VERSION 5.8 ;
BUSBITCHARS "[]" ;
DIVIDERCHAR "/" ;
UNITS
    DATABASE MICRONS 1000 ;
END UNITS

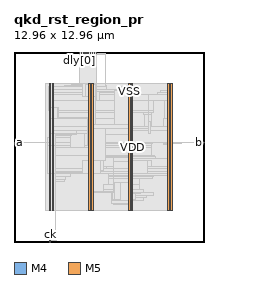
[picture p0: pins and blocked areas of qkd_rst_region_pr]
MACRO qkd_rst_region_pr
  FOREIGN qkd_rst_region_pr 0 0 ;
  CLASS BLOCK ;
  SIZE 12.96 BY 12.96 ;
  PIN a
    DIRECTION INPUT ;
    USE SIGNAL ;
    PORT
      LAYER M4 ;
        RECT  0 6.768 0.084 6.792 ;
    END
  END a
  PIN b
    DIRECTION OUTPUT ;
    USE SIGNAL ;
    PORT
      LAYER M4 ;
        RECT  12.876 6.768 12.96 6.792 ;
    END
  END b
  PIN ck
    DIRECTION INPUT ;
    USE SIGNAL ;
    PORT
      LAYER M5 ;
        RECT  2.448 0 2.472 0.084 ;
    END
  END ck
  PIN dly[0]
    DIRECTION INPUT ;
    USE SIGNAL ;
    PORT
      LAYER M5 ;
        RECT  4.464 12.876 4.488 12.96 ;
    END
  END dly[0]
  PIN dly[1]
    DIRECTION INPUT ;
    USE SIGNAL ;
    PORT
      LAYER M5 ;
        RECT  4.608 12.876 4.632 12.96 ;
    END
  END dly[1]
  PIN dly[2]
    DIRECTION INPUT ;
    USE SIGNAL ;
    PORT
      LAYER M5 ;
        RECT  4.752 12.876 4.776 12.96 ;
    END
  END dly[2]
  PIN dly[3]
    DIRECTION INPUT ;
    USE SIGNAL ;
    PORT
      LAYER M5 ;
        RECT  4.896 12.876 4.92 12.96 ;
    END
  END dly[3]
  PIN dly[4]
    DIRECTION INPUT ;
    USE SIGNAL ;
    PORT
      LAYER M5 ;
        RECT  5.04 12.876 5.064 12.96 ;
    END
  END dly[4]
  PIN dly[5]
    DIRECTION INPUT ;
    USE SIGNAL ;
    PORT
      LAYER M5 ;
        RECT  5.184 12.876 5.208 12.96 ;
    END
  END dly[5]
  PIN dly[6]
    DIRECTION INPUT ;
    USE SIGNAL ;
    PORT
      LAYER M5 ;
        RECT  5.328 12.876 5.352 12.96 ;
    END
  END dly[6]
  PIN dly[7]
    DIRECTION INPUT ;
    USE SIGNAL ;
    PORT
      LAYER M5 ;
        RECT  5.472 12.876 5.496 12.96 ;
    END
  END dly[7]
  PIN por_n
    DIRECTION INPUT ;
    USE SIGNAL ;
    PORT
      LAYER M5 ;
        RECT  5.616 12.876 5.64 12.96 ;
    END
  END por_n
  PIN VDD
    DIRECTION INOUT ;
    USE POWER ;
    PORT
      LAYER M5 ;
        RECT  10.692 2.151 10.812 10.809 ;
        RECT  7.992 2.151 8.112 10.809 ;
        RECT  5.292 2.151 5.412 10.809 ;
        RECT  2.592 2.151 2.712 10.809 ;
    END
  END VDD
  PIN VSS
    DIRECTION INOUT ;
    USE GROUND ;
    PORT
      LAYER M5 ;
        RECT  10.5 2.137 10.62 10.823 ;
        RECT  7.8 2.137 7.92 10.823 ;
        RECT  5.1 2.137 5.22 10.823 ;
        RECT  2.4 2.137 2.52 10.823 ;
    END
  END VSS
  OBS
    LAYER RVTN ;
     RECT  2.16 2.16 10.8 2.295 ;
     RECT  2.16 2.565 10.8 2.835 ;
     RECT  2.16 3.105 10.8 3.375 ;
     RECT  2.16 3.645 10.8 3.915 ;
     RECT  2.16 4.185 10.8 4.455 ;
     RECT  2.16 4.725 10.8 4.995 ;
     RECT  2.16 5.265 10.8 5.535 ;
     RECT  2.16 5.805 10.8 6.075 ;
     RECT  2.16 6.345 10.8 6.615 ;
     RECT  2.16 6.885 10.8 7.155 ;
     RECT  2.16 7.425 10.8 7.695 ;
     RECT  2.16 7.965 10.8 8.235 ;
     RECT  2.16 8.505 10.8 8.775 ;
     RECT  2.16 9.045 10.8 9.315 ;
     RECT  2.16 9.585 10.8 9.855 ;
     RECT  2.16 10.125 10.8 10.395 ;
     RECT  2.16 10.665 10.8 10.8 ;
    LAYER RVTP ;
     RECT  2.16 2.295 10.8 2.565 ;
     RECT  2.16 2.835 10.8 3.105 ;
     RECT  2.16 3.375 10.8 3.645 ;
     RECT  2.16 3.915 10.8 4.185 ;
     RECT  2.16 4.455 10.8 4.725 ;
     RECT  2.16 4.995 10.8 5.265 ;
     RECT  2.16 5.535 10.8 5.805 ;
     RECT  2.16 6.075 10.8 6.345 ;
     RECT  2.16 6.615 10.8 6.885 ;
     RECT  2.16 7.155 10.8 7.425 ;
     RECT  2.16 7.695 10.8 7.965 ;
     RECT  2.16 8.235 10.8 8.505 ;
     RECT  2.16 8.775 10.8 9.045 ;
     RECT  2.16 9.315 10.8 9.585 ;
     RECT  2.16 9.855 10.8 10.125 ;
     RECT  2.16 10.395 10.8 10.665 ;
    LAYER M1 ;
     RECT  2.16 2.151 10.8 10.809 ;
    LAYER M2 ;
     RECT  2.16 2.151 10.8 10.809 ;
     RECT  10.8 2.421 10.812 10.539 ;
     RECT  10.812 6.696 11.435 6.714 ;
    LAYER M3 ;
     RECT  2.415 2.143 2.505 2.413 ;
     RECT  5.115 2.143 5.205 2.413 ;
     RECT  7.815 2.143 7.905 2.413 ;
     RECT  10.515 2.143 10.605 2.413 ;
     RECT  7.815 2.413 8.097 2.569 ;
     RECT  6.804 2.569 8.097 2.641 ;
     RECT  6.66 2.641 8.097 2.839 ;
     RECT  6.66 2.839 8.802 3.037 ;
     RECT  6.66 3.037 9.054 3.181 ;
     RECT  6.66 3.181 9.522 3.403 ;
     RECT  6.12 3.403 9.522 3.407 ;
     RECT  6.12 3.407 8.838 3.569 ;
     RECT  6.12 3.569 8.586 3.911 ;
     RECT  2.415 2.413 2.697 4.117 ;
     RECT  2.415 4.117 3.33 4.153 ;
     RECT  2.415 4.153 3.438 4.261 ;
     RECT  6.444 3.911 8.586 4.351 ;
     RECT  2.415 4.261 3.546 4.495 ;
     RECT  6.444 4.351 9.45 4.495 ;
     RECT  6.444 4.495 9.522 4.531 ;
     RECT  10.515 2.413 10.797 4.531 ;
     RECT  5.115 2.413 5.397 4.657 ;
     RECT  6.444 4.531 10.797 4.657 ;
     RECT  5.115 4.657 10.797 4.699 ;
     RECT  2.415 4.495 3.834 4.801 ;
     RECT  4.716 4.699 10.797 4.801 ;
     RECT  2.415 4.801 10.797 5.027 ;
     RECT  6.336 5.027 10.797 5.729 ;
     RECT  6.336 5.729 9.63 5.837 ;
     RECT  6.336 5.837 9.558 5.873 ;
     RECT  2.415 5.027 5.598 5.881 ;
     RECT  6.336 5.873 9.378 5.881 ;
     RECT  2.415 5.881 9.378 6.449 ;
     RECT  2.415 6.449 3.87 6.571 ;
     RECT  4.788 6.449 9.378 6.605 ;
     RECT  10.515 5.729 10.797 6.655 ;
     RECT  5.115 6.605 9.378 6.691 ;
     RECT  10.188 6.655 10.797 6.691 ;
     RECT  2.412 6.571 3.87 6.763 ;
     RECT  10.188 6.691 11.43 6.797 ;
     RECT  5.115 6.691 9.45 6.817 ;
     RECT  10.188 6.797 10.797 6.817 ;
     RECT  2.304 6.763 3.87 7.115 ;
     RECT  2.415 7.115 3.87 7.231 ;
     RECT  2.415 7.231 3.906 7.357 ;
     RECT  2.415 7.357 4.23 7.591 ;
     RECT  5.115 6.817 10.797 7.591 ;
     RECT  2.415 7.591 10.797 7.889 ;
     RECT  10.224 7.889 10.797 8.429 ;
     RECT  8.892 7.889 9.378 8.671 ;
     RECT  2.415 7.889 8.097 8.851 ;
     RECT  8.82 8.671 9.378 8.851 ;
     RECT  2.415 8.851 9.522 8.941 ;
     RECT  2.376 8.941 9.522 9.661 ;
     RECT  10.26 8.429 10.797 9.661 ;
     RECT  2.376 9.661 10.797 10.049 ;
     RECT  9.216 10.049 10.797 10.085 ;
     RECT  2.376 10.049 8.478 10.229 ;
     RECT  9.756 10.085 10.797 10.229 ;
     RECT  10.008 10.229 10.797 10.355 ;
     RECT  2.376 10.229 8.097 10.427 ;
     RECT  7.092 10.427 8.097 10.463 ;
     RECT  7.164 10.463 8.097 10.547 ;
     RECT  10.515 10.355 10.797 10.547 ;
     RECT  2.376 10.427 6.318 10.589 ;
     RECT  7.164 10.547 7.905 10.589 ;
     RECT  2.376 10.589 2.505 10.625 ;
     RECT  3.24 10.589 5.31 10.625 ;
     RECT  3.42 10.625 5.31 10.661 ;
     RECT  6.228 10.589 6.318 10.661 ;
     RECT  7.704 10.589 7.905 10.661 ;
     RECT  3.924 10.661 5.31 10.769 ;
     RECT  4.248 10.769 5.31 10.781 ;
     RECT  2.415 10.625 2.505 10.817 ;
     RECT  7.815 10.661 7.905 10.817 ;
     RECT  10.515 10.547 10.605 10.817 ;
     RECT  4.248 10.781 5.274 10.829 ;
     RECT  4.572 10.829 5.274 10.973 ;
     RECT  4.572 10.973 4.662 12.029 ;
     RECT  4.644 12.029 4.662 12.845 ;
     RECT  6.228 10.661 6.246 12.845 ;
    LAYER M4 ;
     RECT  0.06 6.768 2.293 6.792 ;
     RECT  2.293 4.704 2.408 4.728 ;
     RECT  2.293 6.576 2.408 6.792 ;
     RECT  2.365 8.976 2.408 9 ;
     RECT  2.408 2.148 2.512 10.812 ;
     RECT  2.512 2.418 2.704 10.542 ;
     RECT  2.437 0.096 2.867 0.12 ;
     RECT  2.704 8.448 3.017 9.144 ;
     RECT  4.561 12 4.589 12.024 ;
     RECT  2.704 4.704 4.705 4.728 ;
     RECT  4.237 10.8 4.705 10.824 ;
     RECT  2.704 7.392 4.777 7.416 ;
     RECT  4.589 12 4.787 12.84 ;
     RECT  4.777 6.576 4.993 7.416 ;
     RECT  3.017 8.448 4.993 8.472 ;
     RECT  4.705 9.936 5.029 10.824 ;
     RECT  4.705 4.704 5.108 5.592 ;
     RECT  4.993 6.576 5.108 8.472 ;
     RECT  5.029 9.936 5.108 10.968 ;
     RECT  5.108 2.148 5.212 10.968 ;
     RECT  5.212 2.418 5.285 10.968 ;
     RECT  5.285 2.418 5.404 10.776 ;
     RECT  5.404 9.504 5.465 10.776 ;
     RECT  4.787 12.768 5.603 12.84 ;
     RECT  5.465 9.648 5.651 10.776 ;
     RECT  5.651 9.648 5.825 10.296 ;
     RECT  5.404 4.704 5.897 5.736 ;
     RECT  5.897 4.896 6.113 5.736 ;
     RECT  5.603 12.816 6.257 12.84 ;
     RECT  5.404 3.408 6.721 3.432 ;
     RECT  6.113 5.136 6.803 5.736 ;
     RECT  6.721 2.88 6.865 3.432 ;
     RECT  6.865 2.88 7.261 4.056 ;
     RECT  7.261 2.832 7.808 4.056 ;
     RECT  6.803 5.52 7.808 5.736 ;
     RECT  5.404 7.344 7.808 8.424 ;
     RECT  5.825 10.272 7.808 10.296 ;
     RECT  7.808 2.148 7.912 10.812 ;
     RECT  7.912 2.418 8.104 10.542 ;
     RECT  8.104 2.88 8.273 3.336 ;
     RECT  8.273 3.312 8.597 3.336 ;
     RECT  8.104 4.656 9.101 5.544 ;
     RECT  8.104 7.728 9.157 7.752 ;
     RECT  9.157 10.032 9.245 10.056 ;
     RECT  9.157 7.392 9.281 8.232 ;
     RECT  9.101 5.136 9.353 5.544 ;
     RECT  9.281 8.208 9.389 8.232 ;
     RECT  9.353 5.136 10.508 5.16 ;
     RECT  10.508 2.148 10.612 10.812 ;
     RECT  10.612 2.418 10.804 10.542 ;
     RECT  10.804 6.768 12.924 6.792 ;
    LAYER M5 ;
     RECT  2.448 0.016 2.472 0.085 ;
     RECT  2.448 0.085 2.856 0.131 ;
     RECT  2.832 0.131 2.856 2.137 ;
     RECT  5.1 2.137 5.22 2.151 ;
     RECT  7.8 2.137 7.92 2.151 ;
     RECT  10.5 2.137 10.62 2.151 ;
     RECT  2.4 2.137 2.856 4.693 ;
     RECT  6.768 3.397 6.792 5.171 ;
     RECT  5.1 2.151 5.412 5.557 ;
     RECT  2.304 4.693 2.856 6.611 ;
     RECT  2.4 6.611 2.856 7.427 ;
     RECT  5.1 5.557 6.264 7.765 ;
     RECT  7.8 2.151 8.112 7.765 ;
     RECT  5.1 7.765 8.112 8.003 ;
     RECT  2.4 7.427 2.712 8.437 ;
     RECT  2.4 8.437 2.952 9.155 ;
     RECT  5.1 8.003 5.592 9.925 ;
     RECT  9.168 7.381 9.192 10.067 ;
     RECT  6.864 8.003 8.112 10.307 ;
     RECT  4.896 9.925 5.592 10.741 ;
     RECT  4.896 10.741 5.64 10.789 ;
     RECT  2.4 9.155 2.712 10.809 ;
     RECT  7.8 10.307 8.112 10.809 ;
     RECT  10.5 2.151 10.812 10.809 ;
     RECT  2.4 10.809 2.52 10.823 ;
     RECT  7.8 10.809 7.92 10.823 ;
     RECT  10.5 10.809 10.62 10.823 ;
     RECT  4.464 10.789 5.64 12.944 ;
  END
END qkd_rst_region_pr
END LIBRARY
